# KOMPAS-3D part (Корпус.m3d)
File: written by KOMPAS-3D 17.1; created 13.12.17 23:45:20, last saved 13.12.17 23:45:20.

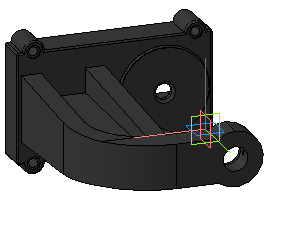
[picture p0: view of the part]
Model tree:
1. Операция без истории:1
